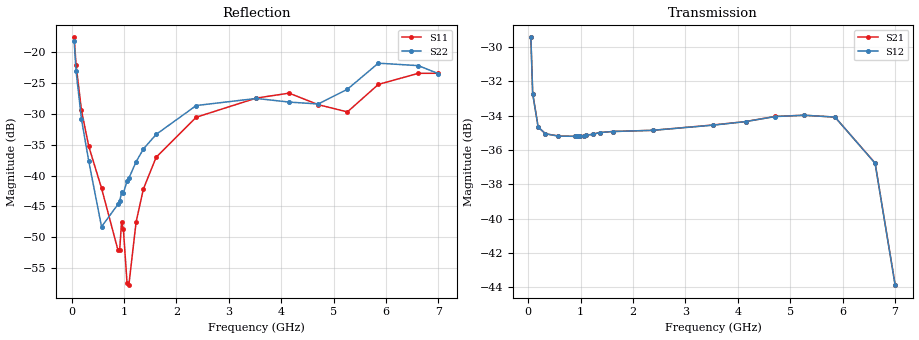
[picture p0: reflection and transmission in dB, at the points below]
! Integrated Device Technology
! Corporate Headquarters
! 6024 Silver Creek Valley Road
! San Jose, CA 95138  USA
! Phone:  1-408-284-8200
! Toll Free:  1-800-223-1366
! Webpage:  http://www.idt.com/
! Timing and RF Division
! 515 Groton Road, Suite 102
! Westford, MA 01886-6024
! Device:  F2258
! Description: Voltage Variable RF Attenuator
! Frequency:  50.0 -  6000.00 MHz
! Package:  3x3 mm Thin QFN Plastic Package: 16 pin
! Ports:  2 RF, 2 DC
!  Pin  1  = NC
!  Pin  2  = NC
!  Pin  3  = RF2  = Port 2
!  Pin  4  = GND
!  Pin  5  = Vdd
!  Pin  6  = NC
!  Pin  7  = VCTRL
!  Pin  8  = NC
!  Pin  9  = GND
!  Pin 10  = RF1  = Port 1
!  Pin 11  = NC
!  Pin 12  = NC
!  Pin 13  = NC
!  Pin 14  = NC
!  Pin 15  = NC
!  Pin 16  = NC
! Vcntrl:  2.080 Volts
! Vdd:  +3.300 Volts
! Current:  1.153 mA
! Data:  The device was measured on a the F2258 evaluation board which has
!  individual transmission lines to the RF pins.  Data was collected
!  using a calibrated network analyzer.  The evaluation board was
!  de-embedded using a TRL calibration technique.
!  The reference plane is the edge of the package pin.
! Misc:  SN 10
!  Action Tracker AT0285
! Date Measured:  2014-12-10
! Date:  2016-01-13  MJV
! Note:
!  Integrated Device Technology supplies this data as a sample of measured
!  data at the package pin for this product.  Your particular data for this
!  product may vary.
!  Data was taken at 25 degrees C.
!  Integrated Device Technology reserves the right to change this data at anytime.
!Freq_(GHz)  S11M_(dB)  S11P_(deg)  S21M_(dB)  S21P_(deg)  S12M_(dB)  S12P_(deg)  S22M_(dB)  S22P_(deg)
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# GHz S dB R 50
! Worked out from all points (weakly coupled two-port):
!   201 points, 50 MHz to 7 GHz, reference 50 ohm
!   highest |S21| = -29.43 dB at 50 MHz (marker M1); lowest = -43.8 dB at 7 GHz (marker M2)
!   lowest |S11| = -57.8 dB at 1.093 GHz (marker M3), VSWR 1.00, Z = 49.9 + j0.111 ohm
!   |S11| at or under -10 dB: start of sweep to end of sweep
!   |S22| runs from -48.9 to -18.2 dB; largest |S21 - S12| = 8.9e-05
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0.05  -17.55 -111.0  -29.43 -67.5  -29.43 -67.5  -18.19 -109.7
0.08475  -21.97 -107.4  -32.71 -47.9  -32.71 -47.9  -22.97 -103.2
0.189  -29.42 -109.4  -34.66 -24.3  -34.66 -24.3  -30.87 -96.8
0.328  -35.27 -115.1  -35.05 -15.2  -35.05 -15.2  -37.68 -88.8
0.57125  -42.04 -125.0  -35.18 -10.3  -35.19 -10.3  -48.30 -26.7
0.884  -52.08 166.4  -35.20 -8.6  -35.20 -8.5  -44.70 47.8
0.91875  -52.02 149.8  -35.19 -8.4  -35.19 -8.5  -44.18 49.5
0.9535  -47.52 -162.5  -35.20 -8.4  -35.20 -8.4  -42.70 78.2
0.98825  -48.70 -173.7  -35.18 -8.3  -35.18 -8.3  -42.84 74.0
1.05775  -57.40 153.9  -35.16 -8.1  -35.17 -8.1  -40.94 61.8
1.0925  -57.80 120.7  -35.14 -8.1  -35.15 -8.1  -40.45 59.9
1.2315  -47.52 46.3  -35.08 -8.2  -35.08 -8.1  -37.75 46.8
1.3705  -42.17 37.1  -34.98 -8.6  -34.98 -8.6  -35.68 41.8
1.61375  -37.02 32.8  -34.92 -9.9  -34.92 -9.9  -33.31 35.0
2.37825  -30.52 48.1  -34.85 -13.6  -34.85 -13.6  -28.62 32.7
3.525  -27.41 91.6  -34.54 -20.2  -34.55 -20.2  -27.47 59.3
4.1505  -26.61 104.9  -34.34 -24.7  -34.34 -24.7  -28.06 68.6
4.7065  -28.48 95.6  -34.04 -29.5  -34.05 -29.4  -28.37 50.9
5.2625  -29.66 54.3  -33.97 -35.6  -33.97 -35.6  -25.98 13.8
5.85325  -25.19 29.9  -34.08 -46.1  -34.08 -46.1  -21.74 -7.1
6.61775  -23.39 49.7  -36.76 -68.8  -36.77 -68.7  -22.14 -48.1
7  -23.38 84.4  -43.85 -62.0  -43.88 -61.7  -23.45 -128.8
